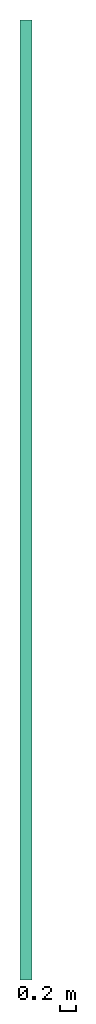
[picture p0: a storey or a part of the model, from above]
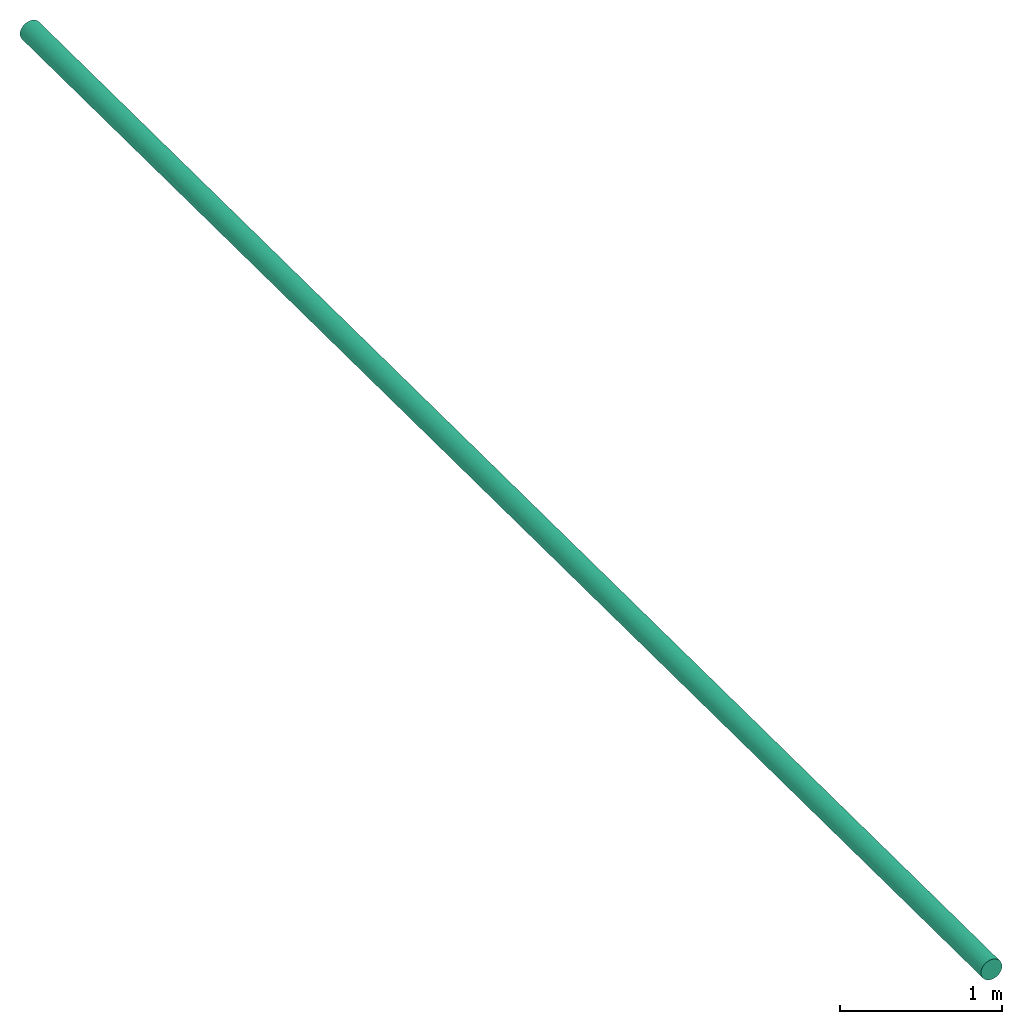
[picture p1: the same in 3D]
Properties of the parts of a building model (IFC2X3), part 1 of 2

# File
Description: ViewDefinition [CoordinationView_V2.0], RevitIdentifiers [ContentGUID: d610ecb9-631b-4e63-a7a0-f926296f45f9, VersionGUID: d526e5fb-8e76-41b3-b54c-00f57d6fdff5, NumberOfSaves: 322], CoordinateReference [CoordinateBase: Coordenadas compartilhadas]
File name: ABADIA_CEPAC_EX_DRE_PE_R01.ifc
Time: 2025-07-22T15:00:02-03:00
Written by: ODA SDAI 24.12
Made in: Autodesk Revit 25.4.0.32 (PTB) - IFC 25.4.0.32

# IfcProject, 01
LongName: CENTRO POLIVALENTE DE ATIVIDADES COMUNITÁRIAS PROF.° NELI ANTÔNIO DOS SANTOS | CEPAC DE ABADIA DE GOIÁS

# IfcSite, Default
RefLatitude: -22, -55, -4, -825807; RefLongitude: -43, -41, -10, -603150; RefElevation: 0 m

# IfcBuilding, CASA DE ACOLHIDA PARA IDOSOS
LongName: CASA DE ACOLHIDA PARA IDOSOS
Pset_BuildingCommon - NumberOfStoreys: 2

# IfcBuildingStorey: Nível:8mm Head (2)
In: CASA DE ACOLHIDA PARA IDOSOS
Name | LongName | Elevation (m)
IMPLANTAÇÃO DRENAGEM | IMPLANTAÇÃO DRENAGEM | -1.75
NIVEL 0 | NIVEL 0 | 0

# IfcBuildingElementProxy: Alvenaria prismática:Alvenaria prismática (3)
In: IMPLANTAÇÃO DRENAGEM
Type - Material: Alvenaria
Pset_BuildingElementProxyCommon - Reference: Alvenaria prismática; sets with these values: 2
Name (Alvenaria prismática:Alvenaria prismática:...)
28310843
28311744
28313048

# IfcBuildingElementProxy: Argamassa Impermeável Rampa (Inspeção):Argamassa Impermeável Rampa (Inspeção) (3)
In: IMPLANTAÇÃO DRENAGEM
Type - Material: Argamassa
Pset_BuildingElementProxyCommon - Reference: Argamassa Impermeável Rampa (Inspeção); sets with these values: 2
Name (Argamassa Impermeável Rampa (Inspeção):Argamassa Impermeável Rampa (Inspeção):...)
28310846
28311747
28313051

# IfcBuildingElementProxy: LXMMPED:LXMMPED, LXMMPED:LXMMPED:28396936
In: IMPLANTAÇÃO DRENAGEM
Type - Material: <Unnamed>
Pset_BuildingElementProxyCommon - Reference: LXMMPED; sets with these values: 2

# IfcBuildingElementProxy: Laje Concreto (Inspeção):Laje Concreto (Inspeção) (3)
In: IMPLANTAÇÃO DRENAGEM
Type - Material: Concreto
Pset_BuildingElementProxyCommon - Reference: Laje Concreto (Inspeção); sets with these values: 2
Name (Laje Concreto (Inspeção):Laje Concreto (Inspeção):...)
28310844
28311745
28313049

# IfcBuildingElementProxy: Tampa de Concreto com Grelha (Inspeção):Tampa de Concreto com Grelha (Inspeção) (3)
In: IMPLANTAÇÃO DRENAGEM
Type - Material: Aço, Concreto
Pset_BuildingElementProxyCommon - Reference: Tampa de Concreto com Grelha (Inspeção); sets with these values: 2
Name (Tampa de Concreto com Grelha (Inspeção):Tampa de Concreto com Grelha (Inspeção):...)
28310845
28311746
28313050

# IfcDistributionPort (886)
Description: Flow
Name | FlowDirection | Group
Port_28303643_0 | SOURCEANDSINK | Outro 1
Port_28303643_1 | SOURCEANDSINK | Outro 1
Port_28304500_0 | SOURCEANDSINK | Outro 2
Port_28304500_1 | SOURCEANDSINK | Outro 2
Port_28304754_0 | SOURCEANDSINK | Outro 5
Port_28304754_1 | SOURCEANDSINK | Outro 5
Port_28304825_0 | SOURCEANDSINK | Outro 4
Port_28304825_1 | SOURCEANDSINK | Outro 4
Port_28304847_0 | SOURCEANDSINK | Outro 8
Port_28304847_1 | SOURCEANDSINK | Outro 8
Port_28304869_0 | SOURCEANDSINK | Outro 10
Port_28304869_1 | SOURCEANDSINK | Outro 10
Port_28304983_0 | SOURCEANDSINK | Outro 7
Port_28304983_1 | SOURCEANDSINK | Outro 7
Port_28304996_0 | SOURCEANDSINK | Outro 9
Port_28304996_1 | SOURCEANDSINK | Outro 9
Port_28305340_0 | SOURCEANDSINK | Outro 18
Port_28305340_1 | SOURCEANDSINK | Outro 18
Port_28308791_0 | SOURCEANDSINK | Outro 17
Port_28308791_1 | SOURCEANDSINK | Outro 17
Port_28309445_0 | SOURCEANDSINK | Outro 6
Port_28309445_1 | SOURCEANDSINK | Outro 6
Port_28309447_0 | SOURCEANDSINK | Outro 11
Port_28309447_1 | SOURCEANDSINK | Outro 11
Port_28309449_0 | SOURCEANDSINK | Outro 12
Port_28309449_1 | SOURCEANDSINK | Outro 12
Port_28309451_0 | SOURCEANDSINK | Outro 13
Port_28309451_1 | SOURCEANDSINK | Outro 13
Port_28309453_0 | SOURCEANDSINK | Outro 14
Port_28309453_1 | SOURCEANDSINK | Outro 14
Port_28309455_0 | SOURCEANDSINK | Outro 15
Port_28309455_1 | SOURCEANDSINK | Outro 15
Port_28309488_0 | SOURCEANDSINK | Outro 16
Port_28309488_1 | SOURCEANDSINK | Outro 16
Port_28309490_0 | SOURCEANDSINK | Outro 19
Port_28309490_1 | SOURCEANDSINK | Outro 19
Port_28309492_0 | SOURCEANDSINK | Outro 20
Port_28309492_1 | SOURCEANDSINK | Outro 20
Port_28309494_0 | SOURCEANDSINK | Outro 21
Port_28309494_1 | SOURCEANDSINK | Outro 21
Port_28309496_0 | SOURCEANDSINK | Outro 22
Port_28309496_1 | SOURCEANDSINK | Outro 22
Port_28309498_0 | SOURCEANDSINK | Outro 23
Port_28309498_1 | SOURCEANDSINK | Outro 23
Port_28309500_0 | SOURCEANDSINK | Outro 24
Port_28309500_1 | SOURCEANDSINK | Outro 24
Port_28309502_0 | SOURCEANDSINK | Outro 25
Port_28309502_1 | SOURCEANDSINK | Outro 25
Port_28309504_0 | SOURCEANDSINK | Outro 26
Port_28309504_1 | SOURCEANDSINK | Outro 26
Port_28309506_0 | SOURCEANDSINK | Outro 27
Port_28309506_1 | SOURCEANDSINK | Outro 27
Port_28309508_0 | SOURCEANDSINK | Outro 28
Port_28309508_1 | SOURCEANDSINK | Outro 28
Port_28309510_0 | SOURCEANDSINK | Outro 29
Port_28309510_1 | SOURCEANDSINK | Outro 29
Port_28309580_0 | SOURCEANDSINK | Outro 30
Port_28309580_1 | SOURCEANDSINK | Outro 30
Port_28311791_0 | SOURCEANDSINK | Pluvial 1
Port_28311791_1 | SOURCEANDSINK | Pluvial 1
Port_28312506_0 | SOURCEANDSINK | Pluvial 2
Port_28312506_1 | SOURCEANDSINK | Pluvial 2
Port_28313325_0 | SOURCEANDSINK | Pluvial 4
Port_28313325_1 | SOURCEANDSINK | Pluvial 4
Port_28313540_0 | SOURCEANDSINK | Pluvial 5
Port_28313540_1 | SOURCEANDSINK | Pluvial 5
Port_28331878_0 | SOURCEANDSINK | Irrigação 1
Port_28368114_2 | SOURCEANDSINK | Irrigação 1
Port_28331878_1 | SOURCEANDSINK | Irrigação 1
Port_28368186_1 | SOURCEANDSINK | Irrigação 1
Port_28331994_0 | SOURCEANDSINK | Irrigação 1
Port_28368186_2 | SOURCEANDSINK | Irrigação 1
Port_28331994_1 | SOURCEANDSINK | Irrigação 1
Port_28332008_2 | SOURCEANDSINK | Irrigação 1
Port_28332002_0 | SOURCEANDSINK | Irrigação 1
Port_28332008_1 | SOURCEANDSINK | Irrigação 1
Port_28332002_1 | SOURCEANDSINK | Irrigação 1
Port_28332204_3 | SOURCEANDSINK | Irrigação 1
Port_28332010_0 | SOURCEANDSINK | Irrigação 1
Port_28360007_1 | SOURCEANDSINK | Irrigação 1
Port_28332010_1 | SOURCEANDSINK | Irrigação 1
Port_28351624_1 | SOURCEANDSINK | Irrigação 1
Port_28332204_1 | SOURCEANDSINK | Irrigação 1
Port_28351550_1 | SOURCEANDSINK | Irrigação 1
Port_28332204_2 | SOURCEANDSINK | Irrigação 1
Port_28332215_1 | SOURCEANDSINK | Irrigação 1
Port_28332215_0 | SOURCEANDSINK | Irrigação 1
Port_28360045_1 | SOURCEANDSINK | Irrigação 1
Port_28350503_1 | SOURCEANDSINK | Água fria e quente - Distribuição 3
Port_28350503_2 | SOURCEANDSINK
Port_28350503_3 | SOURCEANDSINK
Port_28350503_4 | SOURCEANDSINK
Port_28350503_5 | SOURCEANDSINK
OutPort_28350504_1 | SOURCE | Irrigação 13
OutPort_28350504_2 | SOURCE | Irrigação 13
Port_28350506_0 | SOURCEANDSINK | Irrigação 1
Port_28351127_1 | SOURCEANDSINK | Irrigação 1
Port_28350506_1 | SOURCEANDSINK | Irrigação 1
Port_28350508_1 | SOURCEANDSINK | Irrigação 1
Port_28350508_2 | SOURCEANDSINK | Irrigação 1
Port_28350514_0 | SOURCEANDSINK | Irrigação 1
OutPort_28350510_1 | SOURCE | Irrigação 17
OutPort_28350510_2 | SOURCE | Irrigação 17
Port_28350512_1 | SOURCEANDSINK | Irrigação 21
Port_28357601_0 | SOURCEANDSINK | Irrigação 21
Port_28350512_2 | SOURCEANDSINK | Irrigação 21
Port_28350516_0 | SOURCEANDSINK | Irrigação 21
Port_28350514_1 | SOURCEANDSINK | Irrigação 1
Port_28350516_1 | SOURCEANDSINK | Irrigação 21
Port_28351127_2 | SOURCEANDSINK | Irrigação 1
OutPort_28351133_1 | SOURCE | Irrigação 1
Port_28351133_2 | SOURCEANDSINK | Irrigação 1
Port_28359578_0 | SOURCEANDSINK | Irrigação 1
Port_28351550_0 | SOURCEANDSINK | Irrigação 1
Port_28360027_1 | SOURCEANDSINK | Irrigação 1
OutPort_28351624_2 | SOURCE | Irrigação 1
OutPort_28351626_1 | SOURCE | Irrigação 1
Port_28351626_2 | SOURCEANDSINK | Irrigação 1
Port_28357204_4 | SOURCEANDSINK
Port_28357355_1 | SOURCEANDSINK
Port_28357600_1 | SOURCEANDSINK | Irrigação 21
Port_28358009_0 | SOURCEANDSINK | Irrigação 21
Port_28357600_2 | SOURCEANDSINK | Irrigação 21
Port_28357601_1 | SOURCEANDSINK | Irrigação 21
OutPort_28357600_3 | SOURCE | Irrigação 21
Port_28357932_4 | SOURCEANDSINK
Port_28357933_1 | SOURCEANDSINK
Port_28357934_1 | SOURCEANDSINK | Irrigação 21
Port_28357934_2 | SOURCEANDSINK | Irrigação 21
Port_28358009_1 | SOURCEANDSINK | Irrigação 21
OutPort_28357934_3 | SOURCE | Irrigação 21
Port_28358085_4 | SOURCEANDSINK
Port_28358086_1 | SOURCEANDSINK
OutPort_28358087_1 | SOURCE | Irrigação 2
Port_28358087_2 | SOURCEANDSINK | Irrigação 2
Port_28358089_1 | SOURCEANDSINK | Irrigação 2
OutPort_28358087_3 | SOURCE | Irrigação 2
Port_28358089_0 | SOURCEANDSINK | Irrigação 2
Port_28358102_4 | SOURCEANDSINK
Port_28358103_1 | SOURCEANDSINK
OutPort_28358104_1 | SOURCE | Irrigação 3
Port_28358104_2 | SOURCEANDSINK | Irrigação 3
Port_28358106_1 | SOURCEANDSINK | Irrigação 3
OutPort_28358104_3 | SOURCE | Irrigação 3
Port_28358106_0 | SOURCEANDSINK | Irrigação 3
Port_28358117_4 | SOURCEANDSINK
Port_28358118_1 | SOURCEANDSINK
OutPort_28358119_1 | SOURCE | Irrigação 4
Port_28358119_2 | SOURCEANDSINK | Irrigação 4
Port_28358121_1 | SOURCEANDSINK | Irrigação 4
OutPort_28358119_3 | SOURCE | Irrigação 4
Port_28358121_0 | SOURCEANDSINK | Irrigação 4
Port_28358132_4 | SOURCEANDSINK
Port_28358133_1 | SOURCEANDSINK
OutPort_28358134_1 | SOURCE | Irrigação 5
Port_28358134_2 | SOURCEANDSINK | Irrigação 5
Port_28358136_1 | SOURCEANDSINK | Irrigação 5
Port_28358134_3 | SOURCEANDSINK | Irrigação 5
Port_28358136_0 | SOURCEANDSINK | Irrigação 5
Port_28358474_1 | SOURCEANDSINK | Irrigação 5
Port_28358145_4 | SOURCEANDSINK
Port_28358146_1 | SOURCEANDSINK
Port_28358147_1 | SOURCEANDSINK | Irrigação 6
Port_28358212_0 | SOURCEANDSINK | Irrigação 6
Port_28358147_2 | SOURCEANDSINK | Irrigação 6
Port_28358149_1 | SOURCEANDSINK | Irrigação 6
OutPort_28358147_3 | SOURCE | Irrigação 6
Port_28358149_0 | SOURCEANDSINK | Irrigação 6
Port_28358702_1 | SOURCEANDSINK | Irrigação 6
Port_28358208_4 | SOURCEANDSINK
Port_28358209_1 | SOURCEANDSINK
Port_28358212_1 | SOURCEANDSINK | Irrigação 6
Port_28359193_2 | SOURCEANDSINK | Irrigação 6
OutPort_28358474_2 | SOURCE | Irrigação 5
OutPort_28358702_2 | SOURCE | Irrigação 6
OutPort_28359193_1 | SOURCE | Irrigação 6
Port_28359470_1 | SOURCEANDSINK | Água fria e quente - Distribuição 1
Port_28359470_2 | SOURCEANDSINK
Port_28359470_3 | SOURCEANDSINK
Port_28359470_4 | SOURCEANDSINK
Port_28359470_5 | SOURCEANDSINK
OutPort_28359471_1 | SOURCE | Irrigação 7
OutPort_28359471_2 | SOURCE | Irrigação 7
Port_28359473_0 | SOURCEANDSINK | Irrigação 1
Port_28359577_3 | SOURCEANDSINK | Irrigação 1
Port_28359473_1 | SOURCEANDSINK | Irrigação 1
Port_28359475_1 | SOURCEANDSINK | Irrigação 1
Port_28359475_2 | SOURCEANDSINK | Irrigação 1
Port_28359481_0 | SOURCEANDSINK | Irrigação 1
OutPort_28359477_1 | SOURCE | Irrigação 9
OutPort_28359477_2 | SOURCE | Irrigação 9
Port_28359479_1 | SOURCEANDSINK | Irrigação 11
Port_28359488_0 | SOURCEANDSINK | Irrigação 11
Port_28359479_2 | SOURCEANDSINK | Irrigação 11
Port_28359483_0 | SOURCEANDSINK | Irrigação 11
Port_28359481_1 | SOURCEANDSINK | Irrigação 1
Port_28359483_1 | SOURCEANDSINK | Irrigação 11
Port_28359485_4 | SOURCEANDSINK
Port_28359486_1 | SOURCEANDSINK
Port_28359487_1 | SOURCEANDSINK | Irrigação 11
Port_28359495_0 | SOURCEANDSINK | Irrigação 11
Port_28359487_2 | SOURCEANDSINK | Irrigação 11
Port_28359488_1 | SOURCEANDSINK | Irrigação 11
OutPort_28359487_3 | SOURCE | Irrigação 11
Port_28359491_4 | SOURCEANDSINK
Port_28359492_1 | SOURCEANDSINK
OutPort_28359493_1 | SOURCE | Irrigação 11
Port_28359493_2 | SOURCEANDSINK | Irrigação 11
Port_28359495_1 | SOURCEANDSINK | Irrigação 11
OutPort_28359493_3 | SOURCE | Irrigação 11
Port_28359497_4 | SOURCEANDSINK
Port_28359498_1 | SOURCEANDSINK
OutPort_28359499_1 | SOURCE | Irrigação 15
Port_28359499_2 | SOURCEANDSINK | Irrigação 15
Port_28359501_1 | SOURCEANDSINK | Irrigação 15
OutPort_28359499_3 | SOURCE | Irrigação 15
Port_28359501_0 | SOURCEANDSINK | Irrigação 15
Port_28359503_4 | SOURCEANDSINK
Port_28359504_1 | SOURCEANDSINK
OutPort_28359505_1 | SOURCE | Irrigação 18
Port_28359505_2 | SOURCEANDSINK | Irrigação 18
Port_28359507_1 | SOURCEANDSINK | Irrigação 18
OutPort_28359505_3 | SOURCE | Irrigação 18
Port_28359507_0 | SOURCEANDSINK | Irrigação 18
Port_28359509_4 | SOURCEANDSINK
Port_28359510_1 | SOURCEANDSINK
OutPort_28359511_1 | SOURCE | Irrigação 20
Port_28359511_2 | SOURCEANDSINK | Irrigação 20
Port_28359513_1 | SOURCEANDSINK | Irrigação 20
OutPort_28359511_3 | SOURCE | Irrigação 20
Port_28359513_0 | SOURCEANDSINK | Irrigação 20
Port_28359515_4 | SOURCEANDSINK
Port_28359516_1 | SOURCEANDSINK
OutPort_28359517_1 | SOURCE | Irrigação 23
Port_28359517_2 | SOURCEANDSINK | Irrigação 23
Port_28359519_1 | SOURCEANDSINK | Irrigação 23
OutPort_28359517_3 | SOURCE | Irrigação 23
Port_28359519_0 | SOURCEANDSINK | Irrigação 23
Port_28359531_1 | SOURCEANDSINK | Irrigação 23
Port_28359521_4 | SOURCEANDSINK
Port_28359522_1 | SOURCEANDSINK
Port_28359523_1 | SOURCEANDSINK | Irrigação 24
Port_28359529_0 | SOURCEANDSINK | Irrigação 24
Port_28359523_2 | SOURCEANDSINK | Irrigação 24
Port_28359525_1 | SOURCEANDSINK | Irrigação 24
OutPort_28359523_3 | SOURCE | Irrigação 24
Port_28359525_0 | SOURCEANDSINK | Irrigação 24
Port_28359533_1 | SOURCEANDSINK | Irrigação 24
Port_28359527_4 | SOURCEANDSINK
Port_28359528_1 | SOURCEANDSINK
Port_28359529_1 | SOURCEANDSINK | Irrigação 24
Port_28359535_2 | SOURCEANDSINK | Irrigação 24
OutPort_28359531_2 | SOURCE | Irrigação 23
OutPort_28359533_2 | SOURCE | Irrigação 24
OutPort_28359535_1 | SOURCE | Irrigação 24
Port_28359577_1 | SOURCEANDSINK | Irrigação 1
Port_28360046_0 | SOURCEANDSINK | Irrigação 1
Port_28359577_2 | SOURCEANDSINK | Irrigação 1
Port_28359578_1 | SOURCEANDSINK | Irrigação 1
Port_28359605_1 | SOURCEANDSINK | Água fria e quente - Distribuição 2
Port_28359605_2 | SOURCEANDSINK
Port_28359605_3 | SOURCEANDSINK
Port_28359605_4 | SOURCEANDSINK
Port_28359605_5 | SOURCEANDSINK
OutPort_28359606_1 | SOURCE | Irrigação 8
OutPort_28359606_2 | SOURCE | Irrigação 8
Port_28359608_0 | SOURCEANDSINK | Irrigação 1
Port_28360045_3 | SOURCEANDSINK | Irrigação 1
Port_28359608_1 | SOURCEANDSINK | Irrigação 1
Port_28359610_1 | SOURCEANDSINK | Irrigação 1
Port_28359610_2 | SOURCEANDSINK | Irrigação 1
Port_28359616_0 | SOURCEANDSINK | Irrigação 1
OutPort_28359612_1 | SOURCE | Irrigação 12
OutPort_28359612_2 | SOURCE | Irrigação 12
Port_28359614_1 | SOURCEANDSINK | Irrigação 16
Port_28359623_0 | SOURCEANDSINK | Irrigação 16
Port_28359614_2 | SOURCEANDSINK | Irrigação 16
Port_28359618_0 | SOURCEANDSINK | Irrigação 16
Port_28359616_1 | SOURCEANDSINK | Irrigação 1
Port_28359618_1 | SOURCEANDSINK | Irrigação 16
Port_28359620_4 | SOURCEANDSINK
Port_28359621_1 | SOURCEANDSINK
Port_28359622_1 | SOURCEANDSINK | Irrigação 16
Port_28359630_0 | SOURCEANDSINK | Irrigação 16
Port_28359622_2 | SOURCEANDSINK | Irrigação 16
Port_28359623_1 | SOURCEANDSINK | Irrigação 16
OutPort_28359622_3 | SOURCE | Irrigação 16
Port_28359626_4 | SOURCEANDSINK
Port_28359627_1 | SOURCEANDSINK
OutPort_28359628_1 | SOURCE | Irrigação 16
Port_28359628_2 | SOURCEANDSINK | Irrigação 16
Port_28359630_1 | SOURCEANDSINK | Irrigação 16
OutPort_28359628_3 | SOURCE | Irrigação 16
Port_28359632_4 | SOURCEANDSINK
Port_28359633_1 | SOURCEANDSINK
OutPort_28359634_1 | SOURCE | Irrigação 25
Port_28359634_2 | SOURCEANDSINK | Irrigação 25
Port_28359636_1 | SOURCEANDSINK | Irrigação 25
OutPort_28359634_3 | SOURCE | Irrigação 25
Port_28359636_0 | SOURCEANDSINK | Irrigação 25
Port_28359638_4 | SOURCEANDSINK
Port_28359639_1 | SOURCEANDSINK
OutPort_28359640_1 | SOURCE | Irrigação 27
Port_28359640_2 | SOURCEANDSINK | Irrigação 27
Port_28359642_1 | SOURCEANDSINK | Irrigação 27
OutPort_28359640_3 | SOURCE | Irrigação 27
Port_28359642_0 | SOURCEANDSINK | Irrigação 27
Port_28359644_4 | SOURCEANDSINK
Port_28359645_1 | SOURCEANDSINK
OutPort_28359646_1 | SOURCE | Irrigação 29
Port_28359646_2 | SOURCEANDSINK | Irrigação 29
Port_28359648_1 | SOURCEANDSINK | Irrigação 29
OutPort_28359646_3 | SOURCE | Irrigação 29
Port_28359648_0 | SOURCEANDSINK | Irrigação 29
Port_28359650_4 | SOURCEANDSINK
Port_28359651_1 | SOURCEANDSINK
OutPort_28359652_1 | SOURCE | Irrigação 31
Port_28359652_2 | SOURCEANDSINK | Irrigação 31
Port_28359654_1 | SOURCEANDSINK | Irrigação 31
OutPort_28359652_3 | SOURCE | Irrigação 31
Port_28359654_0 | SOURCEANDSINK | Irrigação 31
Port_28359666_1 | SOURCEANDSINK | Irrigação 31
Port_28359656_4 | SOURCEANDSINK
Port_28359657_1 | SOURCEANDSINK
Port_28359658_1 | SOURCEANDSINK | Irrigação 32
Port_28359664_0 | SOURCEANDSINK | Irrigação 32
Port_28359658_2 | SOURCEANDSINK | Irrigação 32
Port_28359660_1 | SOURCEANDSINK | Irrigação 32
OutPort_28359658_3 | SOURCE | Irrigação 32
Port_28359660_0 | SOURCEANDSINK | Irrigação 32
Port_28359668_1 | SOURCEANDSINK | Irrigação 32
Port_28359662_4 | SOURCEANDSINK
Port_28359663_1 | SOURCEANDSINK
Port_28359664_1 | SOURCEANDSINK | Irrigação 32
Port_28359670_2 | SOURCEANDSINK | Irrigação 32
OutPort_28359666_2 | SOURCE | Irrigação 31
OutPort_28359668_2 | SOURCE | Irrigação 32
OutPort_28359670_1 | SOURCE | Irrigação 32
Port_28359702_1 | SOURCEANDSINK | Água fria e quente - Distribuição 4
Port_28359702_2 | SOURCEANDSINK
Port_28359702_3 | SOURCEANDSINK
Port_28359702_4 | SOURCEANDSINK
Port_28359702_5 | SOURCEANDSINK
OutPort_28359703_1 | SOURCE | Irrigação 14
OutPort_28359703_2 | SOURCE | Irrigação 14
Port_28359705_0 | SOURCEANDSINK | Irrigação 1
Port_28360027_3 | SOURCEANDSINK | Irrigação 1
Port_28359705_1 | SOURCEANDSINK | Irrigação 1
Port_28359707_1 | SOURCEANDSINK | Irrigação 1
Port_28359707_2 | SOURCEANDSINK | Irrigação 1
Port_28359713_0 | SOURCEANDSINK | Irrigação 1
OutPort_28359709_1 | SOURCE | Irrigação 22
OutPort_28359709_2 | SOURCE | Irrigação 22
Port_28359711_1 | SOURCEANDSINK | Irrigação 28
Port_28359720_0 | SOURCEANDSINK | Irrigação 28
Port_28359711_2 | SOURCEANDSINK | Irrigação 28
Port_28359715_0 | SOURCEANDSINK | Irrigação 28
Port_28359713_1 | SOURCEANDSINK | Irrigação 1
Port_28359715_1 | SOURCEANDSINK | Irrigação 28
Port_28359717_4 | SOURCEANDSINK
Port_28359718_1 | SOURCEANDSINK
Port_28359719_1 | SOURCEANDSINK | Irrigação 28
Port_28359727_0 | SOURCEANDSINK | Irrigação 28
Port_28359719_2 | SOURCEANDSINK | Irrigação 28
Port_28359720_1 | SOURCEANDSINK | Irrigação 28
OutPort_28359719_3 | SOURCE | Irrigação 28
Port_28359723_4 | SOURCEANDSINK
Port_28359724_1 | SOURCEANDSINK
OutPort_28359725_1 | SOURCE | Irrigação 28
Port_28359725_2 | SOURCEANDSINK | Irrigação 28
Port_28359727_1 | SOURCEANDSINK | Irrigação 28
OutPort_28359725_3 | SOURCE | Irrigação 28
Port_28359729_4 | SOURCEANDSINK
Port_28359730_1 | SOURCEANDSINK
OutPort_28359731_1 | SOURCE | Irrigação 34
Port_28359731_2 | SOURCEANDSINK | Irrigação 34
Port_28359733_1 | SOURCEANDSINK | Irrigação 34
OutPort_28359731_3 | SOURCE | Irrigação 34
Port_28359733_0 | SOURCEANDSINK | Irrigação 34
Port_28359735_4 | SOURCEANDSINK
Port_28359736_1 | SOURCEANDSINK
OutPort_28359737_1 | SOURCE | Irrigação 36
Port_28359737_2 | SOURCEANDSINK | Irrigação 36
Port_28359739_1 | SOURCEANDSINK | Irrigação 36
OutPort_28359737_3 | SOURCE | Irrigação 36
Port_28359739_0 | SOURCEANDSINK | Irrigação 36
Port_28359741_4 | SOURCEANDSINK
Port_28359742_1 | SOURCEANDSINK
OutPort_28359743_1 | SOURCE | Irrigação 38
Port_28359743_2 | SOURCEANDSINK | Irrigação 38
Port_28359745_1 | SOURCEANDSINK | Irrigação 38
OutPort_28359743_3 | SOURCE | Irrigação 38
Port_28359745_0 | SOURCEANDSINK | Irrigação 38
Port_28359747_4 | SOURCEANDSINK
Port_28359748_1 | SOURCEANDSINK
OutPort_28359749_1 | SOURCE | Irrigação 40
Port_28359749_2 | SOURCEANDSINK | Irrigação 40
Port_28359751_1 | SOURCEANDSINK | Irrigação 40
OutPort_28359749_3 | SOURCE | Irrigação 40
Port_28359751_0 | SOURCEANDSINK | Irrigação 40
Port_28359763_1 | SOURCEANDSINK | Irrigação 40
Port_28359753_4 | SOURCEANDSINK
Port_28359754_1 | SOURCEANDSINK
Port_28359755_1 | SOURCEANDSINK | Irrigação 41
Port_28359761_0 | SOURCEANDSINK | Irrigação 41
Port_28359755_2 | SOURCEANDSINK | Irrigação 41
Port_28359757_1 | SOURCEANDSINK | Irrigação 41
OutPort_28359755_3 | SOURCE | Irrigação 41
Port_28359757_0 | SOURCEANDSINK | Irrigação 41
Port_28359765_1 | SOURCEANDSINK | Irrigação 41
Port_28359759_4 | SOURCEANDSINK
Port_28359760_1 | SOURCEANDSINK
Port_28359761_1 | SOURCEANDSINK | Irrigação 41
Port_28359767_2 | SOURCEANDSINK | Irrigação 41
OutPort_28359763_2 | SOURCE | Irrigação 40
OutPort_28359765_2 | SOURCE | Irrigação 41
OutPort_28359767_1 | SOURCE | Irrigação 41
Port_28359799_1 | SOURCEANDSINK | Água fria e quente - Distribuição 5
Port_28359799_2 | SOURCEANDSINK
Port_28359799_3 | SOURCEANDSINK
Port_28359799_4 | SOURCEANDSINK
Port_28359799_5 | SOURCEANDSINK
OutPort_28359800_1 | SOURCE | Irrigação 26
OutPort_28359800_2 | SOURCE | Irrigação 26
Port_28359802_0 | SOURCEANDSINK | Irrigação 1
Port_28360007_3 | SOURCEANDSINK | Irrigação 1
Port_28359802_1 | SOURCEANDSINK | Irrigação 1
Port_28359804_1 | SOURCEANDSINK | Irrigação 1
Port_28359804_2 | SOURCEANDSINK | Irrigação 1
Port_28359810_0 | SOURCEANDSINK | Irrigação 1
OutPort_28359806_1 | SOURCE | Irrigação 33
OutPort_28359806_2 | SOURCE | Irrigação 33
Port_28359808_1 | SOURCEANDSINK | Irrigação 37
Port_28359817_0 | SOURCEANDSINK | Irrigação 37
Port_28359808_2 | SOURCEANDSINK | Irrigação 37
Port_28359812_0 | SOURCEANDSINK | Irrigação 37
Port_28359810_1 | SOURCEANDSINK | Irrigação 1
Port_28359812_1 | SOURCEANDSINK | Irrigação 37
Port_28359814_4 | SOURCEANDSINK
Port_28359815_1 | SOURCEANDSINK
Port_28359816_1 | SOURCEANDSINK | Irrigação 37
Port_28359824_0 | SOURCEANDSINK | Irrigação 37
Port_28359816_2 | SOURCEANDSINK | Irrigação 37
Port_28359817_1 | SOURCEANDSINK | Irrigação 37
OutPort_28359816_3 | SOURCE | Irrigação 37
Port_28359820_4 | SOURCEANDSINK
Port_28359821_1 | SOURCEANDSINK
OutPort_28359822_1 | SOURCE | Irrigação 37
Port_28359822_2 | SOURCEANDSINK | Irrigação 37
Port_28359824_1 | SOURCEANDSINK | Irrigação 37
OutPort_28359822_3 | SOURCE | Irrigação 37
Port_28359826_4 | SOURCEANDSINK
Port_28359827_1 | SOURCEANDSINK
OutPort_28359828_1 | SOURCE | Irrigação 43
Port_28359828_2 | SOURCEANDSINK | Irrigação 43
Port_28359830_1 | SOURCEANDSINK | Irrigação 43
OutPort_28359828_3 | SOURCE | Irrigação 43
Port_28359830_0 | SOURCEANDSINK | Irrigação 43
Port_28359832_4 | SOURCEANDSINK
Port_28359833_1 | SOURCEANDSINK
OutPort_28359834_1 | SOURCE | Irrigação 45
Port_28359834_2 | SOURCEANDSINK | Irrigação 45
Port_28359836_1 | SOURCEANDSINK | Irrigação 45
OutPort_28359834_3 | SOURCE | Irrigação 45
Port_28359836_0 | SOURCEANDSINK | Irrigação 45
Port_28359838_4 | SOURCEANDSINK
Port_28359839_1 | SOURCEANDSINK
OutPort_28359840_1 | SOURCE | Irrigação 47
Port_28359840_2 | SOURCEANDSINK | Irrigação 47
Port_28359842_1 | SOURCEANDSINK | Irrigação 47
OutPort_28359840_3 | SOURCE | Irrigação 47
Port_28359842_0 | SOURCEANDSINK | Irrigação 47
Port_28359844_4 | SOURCEANDSINK
Port_28359845_1 | SOURCEANDSINK
OutPort_28359846_1 | SOURCE | Irrigação 49
Port_28359846_2 | SOURCEANDSINK | Irrigação 49
Port_28359848_1 | SOURCEANDSINK | Irrigação 49
OutPort_28359846_3 | SOURCE | Irrigação 49
Port_28359848_0 | SOURCEANDSINK | Irrigação 49
Port_28359860_1 | SOURCEANDSINK | Irrigação 49
Port_28359850_4 | SOURCEANDSINK
Port_28359851_1 | SOURCEANDSINK
Port_28359852_1 | SOURCEANDSINK | Irrigação 50
Port_28359858_0 | SOURCEANDSINK | Irrigação 50
Port_28359852_2 | SOURCEANDSINK | Irrigação 50
Port_28359854_1 | SOURCEANDSINK | Irrigação 50
OutPort_28359852_3 | SOURCE | Irrigação 50
Port_28359854_0 | SOURCEANDSINK | Irrigação 50
Port_28359862_1 | SOURCEANDSINK | Irrigação 50
Port_28359856_4 | SOURCEANDSINK
Port_28359857_1 | SOURCEANDSINK
Port_28359858_1 | SOURCEANDSINK | Irrigação 50
Port_28359864_2 | SOURCEANDSINK | Irrigação 50
OutPort_28359860_2 | SOURCE | Irrigação 49
OutPort_28359862_2 | SOURCE | Irrigação 50
OutPort_28359864_1 | SOURCE | Irrigação 50
Port_28359896_1 | SOURCEANDSINK | Água fria e quente - Distribuição 6
Port_28359896_2 | SOURCEANDSINK
Port_28359896_3 | SOURCEANDSINK
Port_28359896_4 | SOURCEANDSINK
Port_28359896_5 | SOURCEANDSINK
OutPort_28359897_1 | SOURCE | Irrigação 35
OutPort_28359897_2 | SOURCE | Irrigação 35
Port_28359899_0 | SOURCEANDSINK | Irrigação 39
Port_28359899_1 | SOURCEANDSINK | Irrigação 39
Port_28359901_1 | SOURCEANDSINK | Irrigação 39
Port_28359901_2 | SOURCEANDSINK | Irrigação 39
Port_28359907_0 | SOURCEANDSINK | Irrigação 39
OutPort_28359903_1 | SOURCE | Irrigação 42
OutPort_28359903_2 | SOURCE | Irrigação 42
Port_28359905_1 | SOURCEANDSINK | Irrigação 46
Port_28359914_0 | SOURCEANDSINK | Irrigação 46
Port_28359905_2 | SOURCEANDSINK | Irrigação 46
Port_28359909_0 | SOURCEANDSINK | Irrigação 46
Port_28359907_1 | SOURCEANDSINK | Irrigação 39
Port_28359909_1 | SOURCEANDSINK | Irrigação 46
Port_28359911_4 | SOURCEANDSINK
Port_28359912_1 | SOURCEANDSINK
Port_28359913_1 | SOURCEANDSINK | Irrigação 46
Port_28359921_0 | SOURCEANDSINK | Irrigação 46
Port_28359913_2 | SOURCEANDSINK | Irrigação 46
Port_28359914_1 | SOURCEANDSINK | Irrigação 46
OutPort_28359913_3 | SOURCE | Irrigação 46
Port_28359917_4 | SOURCEANDSINK
Port_28359918_1 | SOURCEANDSINK
OutPort_28359919_1 | SOURCE | Irrigação 46
Port_28359919_2 | SOURCEANDSINK | Irrigação 46
Port_28359921_1 | SOURCEANDSINK | Irrigação 46
OutPort_28359919_3 | SOURCE | Irrigação 46
Port_28359923_4 | SOURCEANDSINK
Port_28359924_1 | SOURCEANDSINK
OutPort_28359925_1 | SOURCE | Irrigação 52
Port_28359925_2 | SOURCEANDSINK | Irrigação 52
Port_28359927_1 | SOURCEANDSINK | Irrigação 52
OutPort_28359925_3 | SOURCE | Irrigação 52
Port_28359927_0 | SOURCEANDSINK | Irrigação 52
Port_28359929_4 | SOURCEANDSINK
Port_28359930_1 | SOURCEANDSINK
OutPort_28359931_1 | SOURCE | Irrigação 54
Port_28359931_2 | SOURCEANDSINK | Irrigação 54
Port_28359933_1 | SOURCEANDSINK | Irrigação 54
OutPort_28359931_3 | SOURCE | Irrigação 54
Port_28359933_0 | SOURCEANDSINK | Irrigação 54
Port_28359935_4 | SOURCEANDSINK
Port_28359936_1 | SOURCEANDSINK
OutPort_28359937_1 | SOURCE | Irrigação 56
Port_28359937_2 | SOURCEANDSINK | Irrigação 56
Port_28359939_1 | SOURCEANDSINK | Irrigação 56
OutPort_28359937_3 | SOURCE | Irrigação 56
Port_28359939_0 | SOURCEANDSINK | Irrigação 56
Port_28359941_4 | SOURCEANDSINK
Port_28359942_1 | SOURCEANDSINK
OutPort_28359943_1 | SOURCE | Irrigação 58
Port_28359943_2 | SOURCEANDSINK | Irrigação 58
Port_28359945_1 | SOURCEANDSINK | Irrigação 58
OutPort_28359943_3 | SOURCE | Irrigação 58
Port_28359945_0 | SOURCEANDSINK | Irrigação 58
Port_28359957_1 | SOURCEANDSINK | Irrigação 58
Port_28359947_4 | SOURCEANDSINK
Port_28359948_1 | SOURCEANDSINK
Port_28359949_1 | SOURCEANDSINK | Irrigação 59
Port_28359955_0 | SOURCEANDSINK | Irrigação 59
Port_28359949_2 | SOURCEANDSINK | Irrigação 59
Port_28359951_1 | SOURCEANDSINK | Irrigação 59
OutPort_28359949_3 | SOURCE | Irrigação 59
Port_28359951_0 | SOURCEANDSINK | Irrigação 59
Port_28359959_1 | SOURCEANDSINK | Irrigação 59
Port_28359953_4 | SOURCEANDSINK
Port_28359954_1 | SOURCEANDSINK
Port_28359955_1 | SOURCEANDSINK | Irrigação 59
Port_28359961_2 | SOURCEANDSINK | Irrigação 59
OutPort_28359957_2 | SOURCE | Irrigação 58
OutPort_28359959_2 | SOURCE | Irrigação 59
OutPort_28359961_1 | SOURCE | Irrigação 59
Port_28360007_2 | SOURCEANDSINK | Irrigação 1
Port_28360028_0 | SOURCEANDSINK | Irrigação 1
Port_28360027_2 | SOURCEANDSINK | Irrigação 1
Port_28360028_1 | SOURCEANDSINK | Irrigação 1
Port_28360045_2 | SOURCEANDSINK | Irrigação 1
Port_28360046_1 | SOURCEANDSINK | Irrigação 1
OutPort_28360117_1 | SOURCE
Port_28360117_2 | SOURCEANDSINK | Água fria e quente - Distribuição 8
Port_28371629_0 | SOURCEANDSINK | Água fria e quente - Distribuição 8
Port_28360117_3 | SOURCEANDSINK | Água fria e quente - Distribuição 9
Port_28371257_0 | SOURCEANDSINK | Água fria e quente - Distribuição 9
OutPort_28360117_4 | SOURCE
OutPort_28360117_5 | SOURCE | Água fria e quente - Distribuição 11
InPort_28370632_0 | SINK | Água fria e quente - Distribuição 8
OutPort_28360117_6 | SOURCE | Água fria e quente - Distribuição 8
InPort_28362233_0 | SINK | Água fria e quente - Distribuição 8
OutPort_28360117_7 | SOURCE | Água fria e quente - Distribuição 8
OutPort_28360117_8 | SOURCE | Água fria e quente - Distribuição 7
Port_28360371_1 | SOURCEANDSINK
Port_28360375_1 | SOURCEANDSINK
OutPort_28360491_1 | SOURCE
Port_28360491_2 | SOURCEANDSINK | Água fria e quente - Distribuição 8
Port_28362430_1 | SOURCEANDSINK | Água fria e quente - Distribuição 8
OutPort_28360491_3 | SOURCE
Port_28360491_4 | SOURCEANDSINK | Água fria e quente - Distribuição 9
Port_28371298_0 | SOURCEANDSINK | Água fria e quente - Distribuição 9
OutPort_28360491_5 | SOURCE
InPort_28362357_1 | SINK | Água fria e quente - Distribuição 8
OutPort_28360491_6 | SOURCE | Água fria e quente - Distribuição 8
OutPort_28360491_7 | SOURCE | Água fria e quente - Distribuição 10
InPort_28362200_0 | SINK | Água fria e quente - Distribuição 8
OutPort_28360491_8 | SOURCE | Água fria e quente - Distribuição 8
Port_28360496_1 | SOURCEANDSINK
InPort_28362092_0 | SINK | Água fria e quente - Distribuição 8
OutPort_28362231_1 | SOURCE | Água fria e quente - Distribuição 8
InPort_28370257_1 | SINK | Água fria e quente - Distribuição 8
OutPort_28362092_1 | SOURCE | Água fria e quente - Distribuição 8
InPort_28362131_0 | SINK | Água fria e quente - Distribuição 8
OutPort_28362198_1 | SOURCE | Água fria e quente - Distribuição 8
InPort_28370259_2 | SINK | Água fria e quente - Distribuição 8
OutPort_28362131_1 | SOURCE | Água fria e quente - Distribuição 8
InPort_28362198_2 | SINK | Água fria e quente - Distribuição 8
OutPort_28362200_1 | SOURCE | Água fria e quente - Distribuição 8
InPort_28362231_2 | SINK | Água fria e quente - Distribuição 8
OutPort_28362233_1 | SOURCE | Água fria e quente - Distribuição 8
InPort_28370612_1 | SINK | Água fria e quente - Distribuição 8
OutPort_28362357_0 | SOURCE | Água fria e quente - Distribuição 8
Port_28362430_0 | SOURCEANDSINK | Água fria e quente - Distribuição 8
Port_28371628_1 | SOURCEANDSINK | Água fria e quente - Distribuição 8
InPort_28362554_1 | SINK | Água fria e quente - Distribuição 8
OutPort_28362555_1 | SOURCE | Água fria e quente - Distribuição 8
InPort_28362554_2 | SINK | Água fria e quente - Distribuição 8
OutPort_28370614_0 | SOURCE | Água fria e quente - Distribuição 8
InPort_28362955_0 | SINK | Água fria e quente - Distribuição 8
OutPort_28362554_3 | SOURCE | Água fria e quente - Distribuição 8
InPort_28362555_0 | SINK | Água fria e quente - Distribuição 8
OutPort_28370630_1 | SOURCE | Água fria e quente - Distribuição 8
InPort_28362969_1 | SINK | Água fria e quente - Distribuição 8
OutPort_28362955_1 | SOURCE | Água fria e quente - Distribuição 8
InPort_28362961_0 | SINK | Água fria e quente - Distribuição 8
OutPort_28370936_1 | SOURCE | Água fria e quente - Distribuição 8
InPort_28362979_2 | SINK | Água fria e quente - Distribuição 8
OutPort_28362961_1 | SOURCE | Água fria e quente - Distribuição 8
InPort_28370938_0 | SINK | Água fria e quente - Distribuição 8
OutPort_28362969_2 | SOURCE | Água fria e quente - Distribuição 8
InPort_28363507_0 | SINK | Água fria e quente - Distribuição 8
OutPort_28362979_1 | SOURCE | Água fria e quente - Distribuição 8
InPort_28363414_0 | SINK | Água fria e quente - Distribuição 8
OutPort_28363578_2 | SOURCE | Água fria e quente - Distribuição 8
InPort_28363624_1 | SINK | Água fria e quente - Distribuição 8
OutPort_28363414_1 | SOURCE | Água fria e quente - Distribuição 8
InPort_28363578_1 | SINK | Água fria e quente - Distribuição 8
OutPort_28363507_1 | SOURCE | Água fria e quente - Distribuição 8
InPort_28363627_1 | SINK | Água fria e quente - Distribuição 8
OutPort_28363624_2 | SOURCE | Água fria e quente - Distribuição 8
OutPort_28363627_0 | SOURCE | Água fria e quente - Distribuição 8
Port_28364081_0 | SOURCEANDSINK | Irrigação 1
Port_28370908_1 | SOURCEANDSINK | Irrigação 1
Port_28364081_1 | SOURCEANDSINK | Irrigação 1
Port_28368110_1 | SOURCEANDSINK | Irrigação 1
Port_28364225_0 | SOURCEANDSINK | Irrigação 1
Port_28368008_2 | SOURCEANDSINK | Irrigação 1
Port_28364225_1 | SOURCEANDSINK | Irrigação 1
Port_28368012_1 | SOURCEANDSINK | Irrigação 1
InPort_28367458_1 | SINK | Água fria e quente - Distribuição 14
OutPort_28367805_1 | SOURCE | Irrigação 1
Port_28367805_2 | SOURCEANDSINK | Irrigação 1
Port_28367874_0 | SOURCEANDSINK | Irrigação 1
Port_28367871_1 | SOURCEANDSINK | Irrigação 1
Port_28367900_0 | SOURCEANDSINK | Irrigação 1
Port_28367871_2 | SOURCEANDSINK | Irrigação 1
Port_28367874_1 | SOURCEANDSINK | Irrigação 1
Port_28367899_1 | SOURCEANDSINK | Irrigação 1
Port_28367900_1 | SOURCEANDSINK | Irrigação 1
Port_28367899_2 | SOURCEANDSINK | Irrigação 1
Port_28367967_0 | SOURCEANDSINK | Irrigação 1
OutPort_28367899_3 | SOURCE | Irrigação 1
Port_28367967_1 | SOURCEANDSINK | Irrigação 1
Port_28368012_2 | SOURCEANDSINK | Irrigação 1
Port_28368008_1 | SOURCEANDSINK | Irrigação 1
Port_28370910_0 | SOURCEANDSINK | Irrigação 1
Port_28368108_0 | SOURCEANDSINK | Irrigação 1
Port_28368110_2 | SOURCEANDSINK | Irrigação 1
Port_28368108_1 | SOURCEANDSINK | Irrigação 1
Port_28368114_1 | SOURCEANDSINK | Irrigação 1
InPort_28370279_2 | SINK | Água fria e quente - Distribuição 8
OutPort_28370243_0 | SOURCE | Água fria e quente - Distribuição 8
InPort_28370243_1 | SINK | Água fria e quente - Distribuição 8
OutPort_28370259_1 | SOURCE | Água fria e quente - Distribuição 8
InPort_28370280_0 | SINK | Água fria e quente - Distribuição 8
OutPort_28370257_2 | SOURCE | Água fria e quente - Distribuição 8
InPort_28370267_0 | SINK | Água fria e quente - Distribuição 8
OutPort_28370279_3 | SOURCE | Água fria e quente - Distribuição 8
InPort_28371173_1 | SINK | Água fria e quente - Distribuição 8
OutPort_28370267_1 | SOURCE | Água fria e quente - Distribuição 8
InPort_28370279_1 | SINK | Água fria e quente - Distribuição 8
OutPort_28370280_1 | SOURCE | Água fria e quente - Distribuição 8
InPort_28370614_1 | SINK | Água fria e quente - Distribuição 8
OutPort_28370612_2 | SOURCE | Água fria e quente - Distribuição 8
InPort_28370630_2 | SINK | Água fria e quente - Distribuição 8
OutPort_28370632_1 | SOURCE | Água fria e quente - Distribuição 8
Port_28370908_2 | SOURCEANDSINK | Irrigação 1
Port_28370910_1 | SOURCEANDSINK | Irrigação 1
InPort_28370936_2 | SINK | Água fria e quente - Distribuição 8
OutPort_28370938_1 | SOURCE | Água fria e quente - Distribuição 8
Port_28371160_0 | SOURCEANDSINK | Água fria e quente - Distribuição 8
Port_28371464_1 | SOURCEANDSINK | Água fria e quente - Distribuição 8
Port_28371160_1 | SOURCEANDSINK | Água fria e quente - Distribuição 8
Port_28371173_3 | SOURCEANDSINK | Água fria e quente - Distribuição 8
Port_28371173_2 | SOURCEANDSINK | Água fria e quente - Distribuição 8
Port_28371192_0 | SOURCEANDSINK | Água fria e quente - Distribuição 8
Port_28371192_1 | SOURCEANDSINK | Água fria e quente - Distribuição 8
Port_28371257_1 | SOURCEANDSINK | Água fria e quente - Distribuição 9
Port_28371330_1 | SOURCEANDSINK | Água fria e quente - Distribuição 9
Port_28371298_1 | SOURCEANDSINK | Água fria e quente - Distribuição 9
Port_28371332_2 | SOURCEANDSINK | Água fria e quente - Distribuição 9
Port_28371310_0 | SOURCEANDSINK | Água fria e quente - Distribuição 9
Port_28372723_1 | SOURCEANDSINK | Água fria e quente - Distribuição 9
Port_28371310_1 | SOURCEANDSINK | Água fria e quente - Distribuição 9
Port_28371332_1 | SOURCEANDSINK | Água fria e quente - Distribuição 9
Port_28371330_2 | SOURCEANDSINK | Água fria e quente - Distribuição 9
Port_28372724_0 | SOURCEANDSINK | Água fria e quente - Distribuição 9
Port_28371464_2 | SOURCEANDSINK | Água fria e quente - Distribuição 8
Port_28371674_0 | SOURCEANDSINK | Água fria e quente - Distribuição 8
Port_28371603_0 | SOURCEANDSINK | Água fria e quente - Distribuição 8
Port_28371628_3 | SOURCEANDSINK | Água fria e quente - Distribuição 8
Port_28371603_1 | SOURCEANDSINK | Água fria e quente - Distribuição 8
Port_28371736_1 | SOURCEANDSINK | Água fria e quente - Distribuição 8
Port_28371628_2 | SOURCEANDSINK | Água fria e quente - Distribuição 8
Port_28371629_1 | SOURCEANDSINK | Água fria e quente - Distribuição 8
Port_28371674_1 | SOURCEANDSINK | Água fria e quente - Distribuição 8
Port_28371736_2 | SOURCEANDSINK | Água fria e quente - Distribuição 8
Port_28372707_0 | SOURCEANDSINK | Água fria e quente - Distribuição 9
Port_28372723_3 | SOURCEANDSINK | Água fria e quente - Distribuição 9
Port_28372707_1 | SOURCEANDSINK | Água fria e quente - Distribuição 9
Port_28372723_2 | SOURCEANDSINK | Água fria e quente - Distribuição 9
Port_28372724_1 | SOURCEANDSINK | Água fria e quente - Distribuição 9
Port_28396927_1 | SOURCEANDSINK
Port_28396927_2 | SOURCEANDSINK
Port_28396927_3 | SOURCEANDSINK
Port_28396927_4 | SOURCEANDSINK
Port_28403089_1 | SOURCEANDSINK
Port_28403089_2 | SOURCEANDSINK
Port_28413112_1 | SOURCEANDSINK | Outro 45
Port_28413112_2 | SOURCEANDSINK | Outro 45
Port_28413112_3 | SOURCEANDSINK | Outro 45
Port_28413114_1 | SOURCEANDSINK
Port_28413114_2 | SOURCEANDSINK
Port_28413122_1 | SOURCEANDSINK | Outro 46
Port_28413122_2 | SOURCEANDSINK | Outro 46
Port_28413122_3 | SOURCEANDSINK | Outro 46
Port_28413124_1 | SOURCEANDSINK
Port_28413124_2 | SOURCEANDSINK
Port_28413455_1 | SOURCEANDSINK | Outro 43
Port_28413455_2 | SOURCEANDSINK | Outro 43
Port_28413455_3 | SOURCEANDSINK | Outro 43
Port_28413457_1 | SOURCEANDSINK
Port_28413457_2 | SOURCEANDSINK
Port_28413465_1 | SOURCEANDSINK | Outro 44
Port_28413465_2 | SOURCEANDSINK | Outro 44
Port_28413465_3 | SOURCEANDSINK | Outro 44
Port_28413467_1 | SOURCEANDSINK
Port_28413467_2 | SOURCEANDSINK
Port_28413519_1 | SOURCEANDSINK | Outro 41
Port_28413519_2 | SOURCEANDSINK | Outro 41
Port_28413519_3 | SOURCEANDSINK | Outro 41
Port_28413521_1 | SOURCEANDSINK
Port_28413521_2 | SOURCEANDSINK
Port_28413529_1 | SOURCEANDSINK | Outro 42
Port_28413529_2 | SOURCEANDSINK | Outro 42
Port_28413529_3 | SOURCEANDSINK | Outro 42
Port_28413531_1 | SOURCEANDSINK
Port_28413531_2 | SOURCEANDSINK
Port_28413572_1 | SOURCEANDSINK | Outro 39
Port_28413572_2 | SOURCEANDSINK | Outro 39
Port_28413572_3 | SOURCEANDSINK | Outro 39
Port_28413574_1 | SOURCEANDSINK
Port_28413574_2 | SOURCEANDSINK
Port_28413582_1 | SOURCEANDSINK | Outro 40
Port_28413582_2 | SOURCEANDSINK | Outro 40
Port_28413582_3 | SOURCEANDSINK | Outro 40
Port_28413584_1 | SOURCEANDSINK
Port_28413584_2 | SOURCEANDSINK
Port_28413615_1 | SOURCEANDSINK | Outro 37
Port_28413615_2 | SOURCEANDSINK | Outro 37
Port_28413615_3 | SOURCEANDSINK | Outro 37
Port_28413617_1 | SOURCEANDSINK
Port_28413617_2 | SOURCEANDSINK
Port_28413625_1 | SOURCEANDSINK | Outro 38
Port_28413625_2 | SOURCEANDSINK | Outro 38
Port_28413625_3 | SOURCEANDSINK | Outro 38
Port_28413627_1 | SOURCEANDSINK
Port_28413627_2 | SOURCEANDSINK
Port_28413721_1 | SOURCEANDSINK | Outro 47
Port_28413721_2 | SOURCEANDSINK | Outro 47
Port_28413721_3 | SOURCEANDSINK | Outro 47
Port_28413723_1 | SOURCEANDSINK
Port_28413723_2 | SOURCEANDSINK
Port_28413731_1 | SOURCEANDSINK | Outro 48
Port_28413731_2 | SOURCEANDSINK | Outro 48
Port_28413731_3 | SOURCEANDSINK | Outro 48
Port_28413733_1 | SOURCEANDSINK
Port_28413733_2 | SOURCEANDSINK
Port_28413847_1 | SOURCEANDSINK | Outro 31
Port_28413847_2 | SOURCEANDSINK | Outro 31
Port_28413847_3 | SOURCEANDSINK | Outro 31
Port_28413849_1 | SOURCEANDSINK
Port_28413849_2 | SOURCEANDSINK
Port_28413857_1 | SOURCEANDSINK | Outro 32
Port_28413857_2 | SOURCEANDSINK | Outro 32
Port_28413857_3 | SOURCEANDSINK | Outro 32
Port_28413859_1 | SOURCEANDSINK
Port_28413859_2 | SOURCEANDSINK
Port_28413900_1 | SOURCEANDSINK | Outro 33
Port_28413900_2 | SOURCEANDSINK | Outro 33
Port_28413900_3 | SOURCEANDSINK | Outro 33
Port_28413902_1 | SOURCEANDSINK
Port_28413902_2 | SOURCEANDSINK
Port_28413910_1 | SOURCEANDSINK | Outro 34
Port_28413910_2 | SOURCEANDSINK | Outro 34
Port_28413910_3 | SOURCEANDSINK | Outro 34
Port_28413912_1 | SOURCEANDSINK
Port_28413912_2 | SOURCEANDSINK
Port_28413920_1 | SOURCEANDSINK | Outro 35
Port_28413920_2 | SOURCEANDSINK | Outro 35
Port_28413920_3 | SOURCEANDSINK | Outro 35
Port_28413922_1 | SOURCEANDSINK
Port_28413922_2 | SOURCEANDSINK
Port_28413930_1 | SOURCEANDSINK | Outro 36
Port_28413930_2 | SOURCEANDSINK | Outro 36
Port_28413930_3 | SOURCEANDSINK | Outro 36
Port_28413932_1 | SOURCEANDSINK
Port_28413932_2 | SOURCEANDSINK
Port_28413940_1 | SOURCEANDSINK | Outro 49
Port_28413940_2 | SOURCEANDSINK | Outro 49
Port_28413940_3 | SOURCEANDSINK | Outro 49
Port_28413942_1 | SOURCEANDSINK
Port_28413942_2 | SOURCEANDSINK
Port_28413950_1 | SOURCEANDSINK | Outro 50
Port_28413950_2 | SOURCEANDSINK | Outro 50
Port_28413950_3 | SOURCEANDSINK | Outro 50
Port_28413952_1 | SOURCEANDSINK
Port_28413952_2 | SOURCEANDSINK
Port_28413960_1 | SOURCEANDSINK | Outro 51
Port_28413960_2 | SOURCEANDSINK | Outro 51
Port_28413960_3 | SOURCEANDSINK | Outro 51
Port_28413962_1 | SOURCEANDSINK
Port_28413962_2 | SOURCEANDSINK
Port_28413970_1 | SOURCEANDSINK | Outro 52
Port_28413970_2 | SOURCEANDSINK | Outro 52
Port_28413970_3 | SOURCEANDSINK | Outro 52
Port_28413972_1 | SOURCEANDSINK
Port_28413972_2 | SOURCEANDSINK
Port_28413980_1 | SOURCEANDSINK | Outro 53
Port_28413980_2 | SOURCEANDSINK | Outro 53
Port_28413980_3 | SOURCEANDSINK | Outro 53
Port_28413982_1 | SOURCEANDSINK
Port_28413982_2 | SOURCEANDSINK
Port_28413990_1 | SOURCEANDSINK | Outro 54
Port_28413990_2 | SOURCEANDSINK | Outro 54
Port_28413990_3 | SOURCEANDSINK | Outro 54
Port_28413992_1 | SOURCEANDSINK
Port_28413992_2 | SOURCEANDSINK
Port_28414000_1 | SOURCEANDSINK | Outro 55
Port_28414000_2 | SOURCEANDSINK | Outro 55
Port_28414000_3 | SOURCEANDSINK | Outro 55
Port_28414002_1 | SOURCEANDSINK
Port_28414002_2 | SOURCEANDSINK
Port_28414010_1 | SOURCEANDSINK | Outro 56
Port_28414010_2 | SOURCEANDSINK | Outro 56
Port_28414010_3 | SOURCEANDSINK | Outro 56
Port_28414012_1 | SOURCEANDSINK
Port_28414012_2 | SOURCEANDSINK
Port_28414020_1 | SOURCEANDSINK | Outro 57
Port_28414020_2 | SOURCEANDSINK | Outro 57
Port_28414020_3 | SOURCEANDSINK | Outro 57
Port_28414022_1 | SOURCEANDSINK
Port_28414022_2 | SOURCEANDSINK
Port_28414030_1 | SOURCEANDSINK | Outro 58
Port_28414030_2 | SOURCEANDSINK | Outro 58
Port_28414030_3 | SOURCEANDSINK | Outro 58
Port_28414032_1 | SOURCEANDSINK
Port_28414032_2 | SOURCEANDSINK
Port_28415915_0 | SOURCEANDSINK | Pluvial 6
Port_28415915_1 | SOURCEANDSINK | Pluvial 6
Port_28416132_0 | SOURCEANDSINK | Outro 59
Port_28416132_1 | SOURCEANDSINK | Outro 59
Port_28418382_1 | SOURCEANDSINK
Port_28418450_1 | SOURCEANDSINK
Port_28418604_1 | SOURCEANDSINK
Port_28419284_1 | SOURCEANDSINK
Port_28419288_1 | SOURCEANDSINK

# IfcFlowController: AF_Registro Esfera VS:Soldável - 75 mm (6)
In: IMPLANTAÇÃO DRENAGEM
Type - Material: Phenolic Resin, PVC Marrom
Type - Pset_ManufacturerTypeInformation - Manufacturer: © Tigre S/A
Pset_DistributionFlowElementCommon - Reference: Soldável - 75 mm; sets with these values: 2
Name (AF_Registro Esfera VS:Soldável - 75 mm:...) | Group
28362198 | Água fria e quente - Distribuição 8
28362231 | Água fria e quente - Distribuição 8
28370612 | Água fria e quente - Distribuição 8
28370630 | Água fria e quente - Distribuição 8
28370908 | Irrigação 1
28370936 | Água fria e quente - Distribuição 8

# IfcFlowController: AF_Soldavel_Valvula de Retencao:Soldável - 50 mm, AF_Soldavel_Valvula de Retencao:Soldável - 50 mm:28403089
In: IMPLANTAÇÃO DRENAGEM
Type - Material: PVC Marrom
Type - Pset_ManufacturerTypeInformation - Manufacturer: © Tigre S/A
Pset_DistributionFlowElementCommon - Reference: Soldável - 50 mm; sets with these values: 2

# IfcFlowController: Bomba de recalque1:Bomba de recalque, Bomba de recalque1:Bomba de recalque:28362762
In: IMPLANTAÇÃO DRENAGEM
Type - Material: Steel - Franklin Electric - Green
Type - Pset_ManufacturerTypeInformation - Manufacturer: Franklin Electric
Classification: D3040 Distribution Systems (Uniformat)
Pset_DistributionFlowElementCommon - Reference: Bomba de recalque; sets with these values: 2

# IfcFlowController: Manômetro de Pressão:Mostrador de 50 mm - 8 mm, Manômetro de Pressão:Mostrador de 50 mm - 8 mm:28367458
In: IMPLANTAÇÃO DRENAGEM
Type - Material: Aço inox, Plástico preto, Plástico Vermelho, Latão, Vidro Mostrador
Pset_DistributionFlowElementCommon - Reference: Mostrador de 50 mm - 8 mm; sets with these values: 2
Group: Água fria e quente - Distribuição 14

# IfcFlowController: PVB_Professional_Series_10_Round_Valve_Box:10" Round Valve Box (5)
In: IMPLANTAÇÃO DRENAGEM
Type - Material: Black, Green
Pset_DistributionFlowElementCommon - Reference: 10" Round Valve Box; sets with these values: 2
Name (PVB_Professional_Series_10_Round_Valve_Box:10" Round Valve Box:...)
28350502
28359469
28359604
28359798
28359895

# IfcFlowController: Rotor_5000_Series_5006PC:Rain Curtain 5.0 (48)
In: IMPLANTAÇÃO DRENAGEM
Type - Material: Water, Black Plastic, Blue Plastic
Type - Pset_ManufacturerTypeInformation - Manufacturer: Rain Bird
Pset_DistributionFlowElementCommon - Reference: Rain Curtain 5.0; sets with these values: 2
Name (Rotor_5000_Series_5006PC:Rain Curtain 5.0:...)
28357355
28357933
28358086
28358103
28358118
28358133
28358146
28358209
28359486
28359492
28359498
28359504
28359510
28359516
28359522
28359528
28359621
28359627
28359633
28359639
28359645
28359651
28359657
28359663
28359718
28359724
28359730
28359736
28359742
28359748
28359754
28359760
28359815
28359821
28359827
28359833
28359839
28359845
28359851
28359857
28359912
28359918
28359924
28359930
28359936
28359942
28359948
28359954

# IfcFlowController: SA_Series (2):SA-6050 (48)
In: IMPLANTAÇÃO DRENAGEM
Type - Material: PLÁSTICO, PVC Azul
Pset_DistributionFlowElementCommon - Reference: SA-6050; sets with these values: 2
Name (SA_Series (2):SA-6050:...)
28357204
28357932
28358085
28358102
28358117
28358132
28358145
28358208
28359485
28359491
28359497
28359503
28359509
28359515
28359521
28359527
28359620
28359626
28359632
28359638
28359644
28359650
28359656
28359662
28359717
28359723
28359729
28359735
28359741
28359747
28359753
28359759
28359814
28359820
28359826
28359832
28359838
28359844
28359850
28359856
28359911
28359917
28359923
28359929
28359935
28359941
28359947
28359953

# IfcFlowController: Valve_PGA_Series_150PGA:150-PGA (6)
In: IMPLANTAÇÃO DRENAGEM
Type - Material: PVC-U, Aço cromado, <Unnamed>
Pset_DistributionFlowElementCommon - Reference: 150-PGA; sets with these values: 2
Name (Valve_PGA_Series_150PGA:150-PGA:...) | Group
28350503 | Água fria e quente - Distribuição 3
28359470 | Água fria e quente - Distribuição 1
28359605 | Água fria e quente - Distribuição 2
28359702 | Água fria e quente - Distribuição 4
28359799 | Água fria e quente - Distribuição 5
28359896 | Água fria e quente - Distribuição 6

# IfcFlowFitting: AF_Roscavel _Joelho 45_90:Standard (6)
In: IMPLANTAÇÃO DRENAGEM
Type - Material: PVC Branco
Type - Pset_ManufacturerTypeInformation - Manufacturer: © Tigre S/A
Pset_DistributionFlowElementCommon - Reference: Standard; sets with these values: 2
Name (AF_Roscavel _Joelho 45_90:Standard:...) | Group
28359193 | Irrigação 6
28359535 | Irrigação 24
28359670 | Irrigação 32
28359767 | Irrigação 41
28359864 | Irrigação 50
28359961 | Irrigação 59

# IfcFlowFitting: AF_Roscavel_Te_Reducao:Standard (43)
In: IMPLANTAÇÃO DRENAGEM
Type - Material: PVC Branco
Type - Pset_ManufacturerTypeInformation - Manufacturer: © Tigre S/A
Pset_DistributionFlowElementCommon - Reference: Standard; sets with these values: 2
Name (AF_Roscavel_Te_Reducao:Standard:...) | Group
28357600 | Irrigação 21
28357934 | Irrigação 21
28358087 | Irrigação 2
28358104 | Irrigação 3
28358119 | Irrigação 4
28358134 | Irrigação 5
28358147 | Irrigação 6
28359487 | Irrigação 11
28359493 | Irrigação 11
28359499 | Irrigação 15
28359505 | Irrigação 18
28359511 | Irrigação 20
28359517 | Irrigação 23
28359523 | Irrigação 24
28359622 | Irrigação 16
28359628 | Irrigação 16
28359634 | Irrigação 25
28359640 | Irrigação 27
28359646 | Irrigação 29
28359652 | Irrigação 31
28359658 | Irrigação 32
28359719 | Irrigação 28
28359725 | Irrigação 28
28359731 | Irrigação 34
28359737 | Irrigação 36
28359743 | Irrigação 38
28359749 | Irrigação 40
28359755 | Irrigação 41
28359816 | Irrigação 37
28359822 | Irrigação 37
28359828 | Irrigação 43
28359834 | Irrigação 45
28359840 | Irrigação 47
28359846 | Irrigação 49
28359852 | Irrigação 50
28359913 | Irrigação 46
28359919 | Irrigação 46
28359925 | Irrigação 52
28359931 | Irrigação 54
28359937 | Irrigação 56
28359943 | Irrigação 58
28359949 | Irrigação 59
28367899 | Irrigação 1

# IfcFlowFitting: AF_Soldavel_Adaptador Curto com Bolsa e Rosca:Standard (13)
In: IMPLANTAÇÃO DRENAGEM
Type - Material: PVC Marrom
Type - Pset_ManufacturerTypeInformation - Manufacturer: © Tigre S/A
Pset_DistributionFlowElementCommon - Reference: Standard; sets with these values: 2
Name (AF_Soldavel_Adaptador Curto com Bolsa e Rosca:Standard:...) | Group
28350504 | Irrigação 13
28350510 | Irrigação 17
28359471 | Irrigação 7
28359477 | Irrigação 9
28359606 | Irrigação 8
28359612 | Irrigação 12
28359703 | Irrigação 14
28359709 | Irrigação 22
28359800 | Irrigação 26
28359806 | Irrigação 33
28359897 | Irrigação 35
28359903 | Irrigação 42
28367805 | Irrigação 1

# IfcFlowFitting: AF_Soldavel_Bucha de Reducao Curta:Standard (6)
In: IMPLANTAÇÃO DRENAGEM
Type - Material: PVC Marrom
Type - Pset_ManufacturerTypeInformation - Manufacturer: © Tigre S/A
Pset_DistributionFlowElementCommon - Reference: Standard; sets with these values: 2
Name (AF_Soldavel_Bucha de Reducao Curta:Standard:...) | Group
28358702 | Irrigação 6
28359533 | Irrigação 24
28359668 | Irrigação 32
28359765 | Irrigação 41
28359862 | Irrigação 50
28359959 | Irrigação 59

# IfcFlowFitting: AF_Soldavel_Bucha de Reducao Longa:Standard (10)
In: IMPLANTAÇÃO DRENAGEM
Type - Material: PVC Marrom
Type - Pset_ManufacturerTypeInformation - Manufacturer: © Tigre S/A
Pset_DistributionFlowElementCommon - Reference: Standard; sets with these values: 2
Name (AF_Soldavel_Bucha de Reducao Longa:Standard:...) | Group
28351127 | Irrigação 1
28351626 | Irrigação 1
28358474 | Irrigação 5
28359531 | Irrigação 23
28359666 | Irrigação 31
28359763 | Irrigação 40
28359860 | Irrigação 49
28359957 | Irrigação 58
28363578 | Água fria e quente - Distribuição 8
28368012 | Irrigação 1

# IfcFlowFitting: AF_Soldavel_Curva 45_90:Standard (9)
In: IMPLANTAÇÃO DRENAGEM
Type - Material: PVC Marrom
Type - Pset_ManufacturerTypeInformation - Manufacturer: © Tigre S/A
Pset_DistributionFlowElementCommon - Reference: Standard; sets with these values: 2
Name (AF_Soldavel_Curva 45_90:Standard:...) | Group
28332008 | Irrigação 1
28351133 | Irrigação 1
28351624 | Irrigação 1
28362969 | Água fria e quente - Distribuição 8
28362979 | Água fria e quente - Distribuição 8
28368008 | Irrigação 1
28368110 | Irrigação 1
28368114 | Irrigação 1
28368186 | Irrigação 1

# IfcFlowFitting: AF_Soldavel_Joelho 45_90:Standard (6)
In: IMPLANTAÇÃO DRENAGEM
Type - Material: PVC Marrom
Type - Pset_ManufacturerTypeInformation - Manufacturer: © Tigre S/A
Pset_DistributionFlowElementCommon - Reference: Standard; sets with these values: 2
Name (AF_Soldavel_Joelho 45_90:Standard:...) | Group
28370257 | Água fria e quente - Distribuição 8
28370259 | Água fria e quente - Distribuição 8
28371330 | Água fria e quente - Distribuição 9
28371332 | Água fria e quente - Distribuição 9
28371464 | Água fria e quente - Distribuição 8
28371736 | Água fria e quente - Distribuição 8

# IfcFlowFitting: AF_Soldavel_Te_Reducao:Standard (10)
In: IMPLANTAÇÃO DRENAGEM
Type - Material: PVC Marrom
Type - Pset_ManufacturerTypeInformation - Manufacturer: © Tigre S/A
Pset_DistributionFlowElementCommon - Reference: Standard; sets with these values: 2
Name (AF_Soldavel_Te_Reducao:Standard:...) | Group
28332204 | Irrigação 1
28359577 | Irrigação 1
28360007 | Irrigação 1
28360027 | Irrigação 1
28360045 | Irrigação 1
28362554 | Água fria e quente - Distribuição 8
28370279 | Água fria e quente - Distribuição 8
28371173 | Água fria e quente - Distribuição 8
28371628 | Água fria e quente - Distribuição 8
28372723 | Água fria e quente - Distribuição 9

# IfcFlowFitting: AF_Soldavel_Uniao:Standard (14)
In: IMPLANTAÇÃO DRENAGEM
Type - Material: PVC Marrom
Type - Pset_ManufacturerTypeInformation - Manufacturer: © Tigre S/A
Pset_DistributionFlowElementCommon - Reference: Standard; sets with these values: 2
Name (AF_Soldavel_Uniao:Standard:...) | Group
28350508 | Irrigação 1
28350512 | Irrigação 21
28359475 | Irrigação 1
28359479 | Irrigação 11
28359610 | Irrigação 1
28359614 | Irrigação 16
28359707 | Irrigação 1
28359711 | Irrigação 28
28359804 | Irrigação 1
28359808 | Irrigação 37
28359901 | Irrigação 39
28359905 | Irrigação 46
28363624 | Água fria e quente - Distribuição 8
28367871 | Irrigação 1

# IfcFlowFitting: AN_PLUV_Anel de vedação para Conexão Série R:AN_PLUV_Anel de vedação para Conexão Série R (84)
In: IMPLANTAÇÃO DRENAGEM
Type - Material: Borracha
Type - Pset_ManufacturerTypeInformation - Manufacturer: Blukit
Pset_DistributionFlowElementCommon - Reference: AN_PLUV_Anel de vedação para Conexão Série R; sets with these values: 2
Name (AN_PLUV_Anel de vedação para Conexão Série R:AN_PLUV_Anel de vedação para Conexão Série R:...)
28413116
28413118
28413120
28413126
28413128
28413130
28413459
28413461
28413463
28413469
28413471
28413473
28413523
28413525
28413527
28413533
28413535
28413537
28413576
28413578
28413580
28413586
28413588
28413590
28413619
28413621
28413623
28413629
28413631
28413633
28413725
28413727
28413729
28413735
28413737
28413739
28413851
28413853
28413855
28413861
28413863
28413865
28413904
28413906
28413908
28413914
28413916
28413918
28413924
28413926
28413928
28413934
28413936
28413938
28413944
28413946
28413948
28413954
28413956
28413958
28413964
28413966
28413968
28413974
28413976
28413978
28413984
28413986
28413988
28413994
28413996
28413998
28414004
28414006
28414008
28414014
28414016
28414018
28414024
28414026
28414028
28414034
28414036
28414038

# IfcFlowFitting: Adaptador Soldavel com Anel para CxDagua - Fortlev:Standard (8)
In: IMPLANTAÇÃO DRENAGEM
Type - Material: Fortlev - PVC Marrom
Type - Pset_ManufacturerTypeInformation - Manufacturer: Fortlev
Pset_DistributionFlowElementCommon - Reference: Standard; sets with these values: 2
Name (Adaptador Soldavel com Anel para CxDagua - Fortlev:Standard:...)
28360371
28360375
28360496
28418382
28418450
28418604
28419284
28419288

# IfcFlowFitting: PLUV_Serie Reforcada_Luva Simples:Standard (28)
In: IMPLANTAÇÃO DRENAGEM
Type - Material: PVC Bege Pérola
Type - Pset_ManufacturerTypeInformation - Manufacturer: © Tigre S/A
Pset_DistributionFlowElementCommon - Reference: Standard; sets with these values: 2
Name (PLUV_Serie Reforcada_Luva Simples:Standard:...)
28413114
28413124
28413457
28413467
28413521
28413531
28413574
28413584
28413617
28413627
28413723
28413733
28413849
28413859
28413902
28413912
28413922
28413932
28413942
28413952
28413962
28413972
28413982
28413992
28414002
28414012
28414022
28414032

# IfcFlowFitting: PLUV_Serie Reforcada_Te_Juncao:Standard (28)
In: IMPLANTAÇÃO DRENAGEM
Type - Material: PVC Bege Pérola
Type - Pset_ManufacturerTypeInformation - Manufacturer: © Tigre S/A
Pset_DistributionFlowElementCommon - Reference: Standard; sets with these values: 2
Name (PLUV_Serie Reforcada_Te_Juncao:Standard:...) | Group
28413112 | Outro 45
28413122 | Outro 46
28413455 | Outro 43
28413465 | Outro 44
28413519 | Outro 41
28413529 | Outro 42
28413572 | Outro 39
28413582 | Outro 40
28413615 | Outro 37
28413625 | Outro 38
28413721 | Outro 47
28413731 | Outro 48
28413847 | Outro 31
28413857 | Outro 32
28413900 | Outro 33
28413910 | Outro 34
28413920 | Outro 35
28413930 | Outro 36
28413940 | Outro 49
28413950 | Outro 50
28413960 | Outro 51
28413970 | Outro 52
28413980 | Outro 53
28413990 | Outro 54
28414000 | Outro 55
28414010 | Outro 56
28414020 | Outro 57
28414030 | Outro 58

# IfcFlowSegment: Tipos de tubos:AF_Tubo Branco Roscável (18)
In: IMPLANTAÇÃO DRENAGEM
Type - Pset_ManufacturerTypeInformation - Manufacturer: Tigre S.A.
Pset_DistributionFlowElementCommon - Reference: AF_Tubo Branco Roscável; sets with these values: 2
Pset_FlowSegmentDuctSegment - sets with these values: 2
Name (Tipos de tubos:AF_Tubo Branco Roscável:...) | Length (m) | Group
28362092 | 0.108393 | Água fria e quente - Distribuição 8
28362131 | 0.0641547 | Água fria e quente - Distribuição 8
28362200 | 0.106746 | Água fria e quente - Distribuição 8
28362233 | 0.0625071 | Água fria e quente - Distribuição 8
28362430 | 0.4095 | Água fria e quente - Distribuição 8
28370243 | 1.893 | Água fria e quente - Distribuição 8
28370267 | 0.1534 | Água fria e quente - Distribuição 8
28370280 | 1.899 | Água fria e quente - Distribuição 8
28371160 | 0.0775668 | Água fria e quente - Distribuição 8
28371192 | 0.48 | Água fria e quente - Distribuição 8
28371257 | 0.392771 | Água fria e quente - Distribuição 9
28371298 | 0.392771 | Água fria e quente - Distribuição 9
28371310 | 1.90654 | Água fria e quente - Distribuição 9
28371603 | 2.226 | Água fria e quente - Distribuição 8
28371629 | 0.4155 | Água fria e quente - Distribuição 8
28371674 | 2.07297 | Água fria e quente - Distribuição 8
28372707 | 0.6205 | Água fria e quente - Distribuição 9
28372724 | 1.91586 | Água fria e quente - Distribuição 9

# IfcFlowSegment: Tipos de tubos:AF_Tubo Marrom Soldável (92)
In: IMPLANTAÇÃO DRENAGEM
Type - Pset_ManufacturerTypeInformation - Manufacturer: Tigre S.A.
Pset_DistributionFlowElementCommon - Reference: AF_Tubo Marrom Soldável; sets with these values: 2
Pset_FlowSegmentDuctSegment - sets with these values: 2
Name (Tipos de tubos:AF_Tubo Marrom Soldável:...) | Length (m) | Group
28331878 | 6.34029 | Irrigação 1
28331994 | 8.10644 | Irrigação 1
28332002 | 1.42884 | Irrigação 1
28332010 | 13.0307 | Irrigação 1
28332215 | 7.35663 | Irrigação 1
28350506 | 2.53785 | Irrigação 1
28350514 | 0.148344 | Irrigação 1
28350516 | 0.167618 | Irrigação 21
28351550 | 5.62477 | Irrigação 1
28357601 | 3.81879 | Irrigação 21
28358009 | 12.9348 | Irrigação 21
28358089 | 12.9348 | Irrigação 2
28358106 | 12.9348 | Irrigação 3
28358121 | 12.9348 | Irrigação 4
28358136 | 12.9039 | Irrigação 5
28358149 | 12.9584 | Irrigação 6
28358212 | 12.9661 | Irrigação 6
28359473 | 2.6719 | Irrigação 1
28359481 | 0.148344 | Irrigação 1
28359483 | 0.167618 | Irrigação 11
28359488 | 3.81879 | Irrigação 11
28359495 | 12.9348 | Irrigação 11
28359501 | 12.9348 | Irrigação 15
28359507 | 12.9348 | Irrigação 18
28359513 | 12.9348 | Irrigação 20
28359519 | 12.9339 | Irrigação 23
28359525 | 12.9284 | Irrigação 24
28359529 | 12.9336 | Irrigação 24
28359578 | 13.0307 | Irrigação 1
28359608 | 2.6719 | Irrigação 1
28359616 | 0.148344 | Irrigação 1
28359618 | 0.167618 | Irrigação 16
28359623 | 3.81879 | Irrigação 16
28359630 | 12.9348 | Irrigação 16
28359636 | 12.9348 | Irrigação 25
28359642 | 12.9348 | Irrigação 27
28359648 | 12.9348 | Irrigação 29
28359654 | 12.9339 | Irrigação 31
28359660 | 12.9284 | Irrigação 32
28359664 | 12.9336 | Irrigação 32
28359705 | 2.6719 | Irrigação 1
28359713 | 0.148344 | Irrigação 1
28359715 | 0.167618 | Irrigação 28
28359720 | 3.81879 | Irrigação 28
28359727 | 12.9348 | Irrigação 28
28359733 | 12.9348 | Irrigação 34
28359739 | 12.9348 | Irrigação 36
28359745 | 12.9348 | Irrigação 38
28359751 | 12.9339 | Irrigação 40
28359757 | 12.9284 | Irrigação 41
28359761 | 12.9336 | Irrigação 41
28359802 | 2.6719 | Irrigação 1
28359810 | 0.148344 | Irrigação 1
28359812 | 0.167618 | Irrigação 37
28359817 | 3.81879 | Irrigação 37
28359824 | 12.9348 | Irrigação 37
28359830 | 12.9348 | Irrigação 43
28359836 | 12.9348 | Irrigação 45
28359842 | 12.9348 | Irrigação 47
28359848 | 12.9339 | Irrigação 49
28359854 | 12.9284 | Irrigação 50
28359858 | 12.9336 | Irrigação 50
28359899 | 2.6119 | Irrigação 39
28359907 | 0.148344 | Irrigação 39
28359909 | 0.167618 | Irrigação 46
28359914 | 3.81879 | Irrigação 46
28359921 | 12.9348 | Irrigação 46
28359927 | 12.9348 | Irrigação 52
28359933 | 12.9348 | Irrigação 54
28359939 | 12.9348 | Irrigação 56
28359945 | 12.9339 | Irrigação 58
28359951 | 12.9284 | Irrigação 59
28359955 | 12.9336 | Irrigação 59
28360028 | 13.092 | Irrigação 1
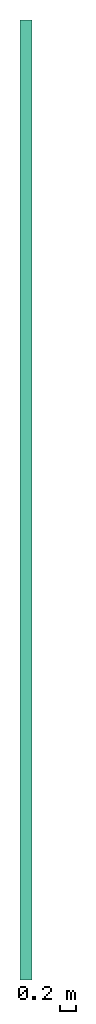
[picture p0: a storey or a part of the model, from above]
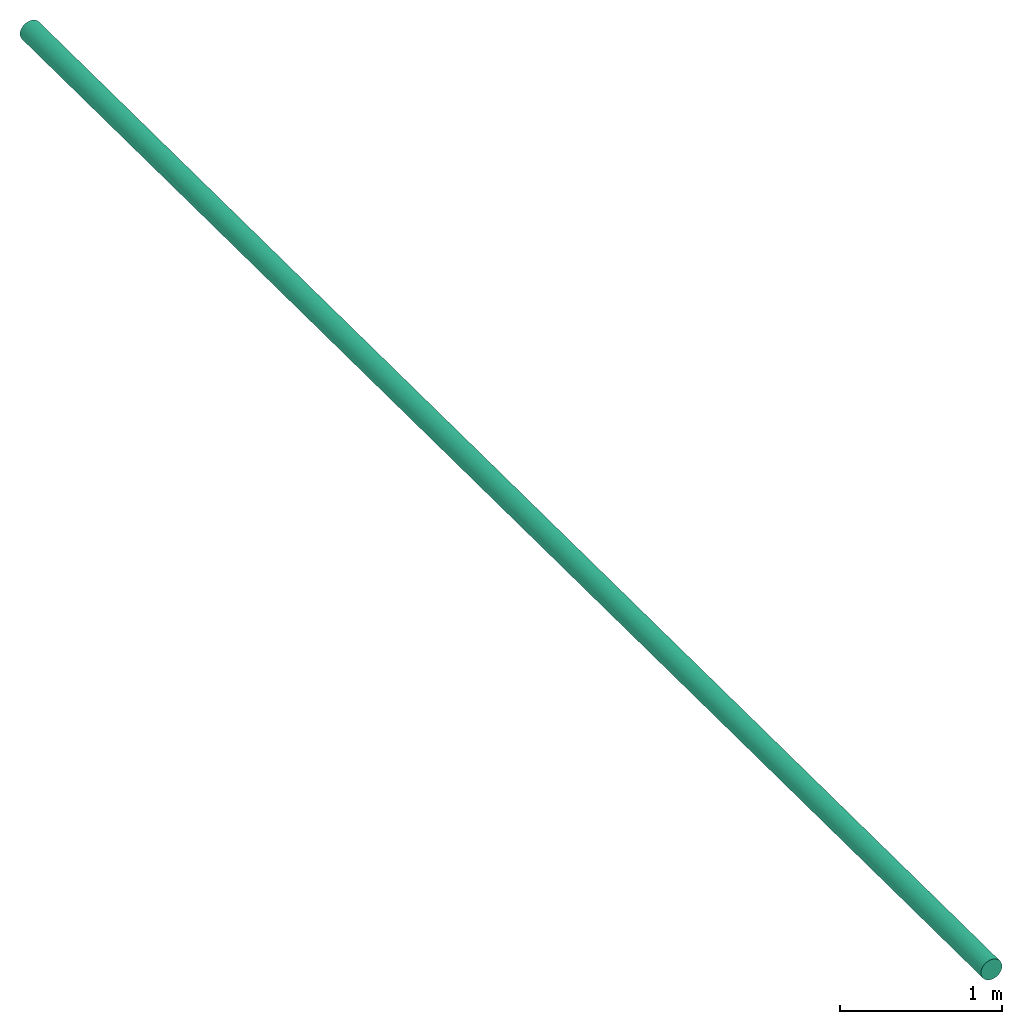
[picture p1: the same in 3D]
Properties of the parts of a building model (IFC2X3), part 2 of 2

# IfcFlowSegment: Tipos de tubos:AF_Tubo Marrom Soldável (92)
Name (Tipos de tubos:AF_Tubo Marrom Soldável:...) | Length (m) | Group
28360046 | 13.092 | Irrigação 1
28362357 | 0.0288581 | Água fria e quente - Distribuição 8
28362555 | 0.232581 | Água fria e quente - Distribuição 8
28362955 | 1.46053 | Água fria e quente - Distribuição 8
28362961 | 0.348745 | Água fria e quente - Distribuição 8
28363414 | 0.0743452 | Água fria e quente - Distribuição 8
28363507 | 0.00500012 | Água fria e quente - Distribuição 8
28363627 | 0.117837 | Água fria e quente - Distribuição 8
28364081 | 0.0921347 | Irrigação 1
28364225 | 0.0295177 | Irrigação 1
28367874 | 0.0486848 | Irrigação 1
28367900 | 0.126415 | Irrigação 1
28367967 | 0.417472 | Irrigação 1
28368108 | 1.16948 | Irrigação 1
28370614 | 0.222072 | Água fria e quente - Distribuição 8
28370632 | 0.0243491 | Água fria e quente - Distribuição 8
28370910 | 0.0512753 | Irrigação 1
28370938 | 6.62746 | Água fria e quente - Distribuição 8

# IfcFlowSegment: Tipos de tubos:PLUV_Tubo PEAD Corrugado (30)
In: IMPLANTAÇÃO DRENAGEM
Type - Pset_ManufacturerTypeInformation - Manufacturer: Tigre S.A.
Pset_DistributionFlowElementCommon - Reference: PLUV_Tubo PEAD Corrugado; sets with these values: 2
Pset_FlowSegmentDuctSegment - sets with these values: 2
Name (Tipos de tubos:PLUV_Tubo PEAD Corrugado:...) | Length (m) | Group
28303643 | 24.4802 | Outro 1
28304500 | 24.4802 | Outro 2
28304754 | 24.4802 | Outro 5
28304825 | 24.4802 | Outro 4
28304847 | 24.4802 | Outro 8
28304869 | 24.4802 | Outro 10
28304983 | 24.4802 | Outro 7
28304996 | 24.4802 | Outro 9
28305340 | 72.297 | Outro 18
28308791 | 24.4802 | Outro 17
28309445 | 24.4802 | Outro 6
28309447 | 24.4802 | Outro 11
28309449 | 24.4802 | Outro 12
28309451 | 24.4802 | Outro 13
28309453 | 24.4802 | Outro 14
28309455 | 24.4802 | Outro 15
28309488 | 24.4802 | Outro 16
28309490 | 24.4802 | Outro 19
28309492 | 24.4802 | Outro 20
28309494 | 24.4802 | Outro 21
28309496 | 24.4802 | Outro 22
28309498 | 24.4802 | Outro 23
28309500 | 24.4802 | Outro 24
28309502 | 24.4802 | Outro 25
28309504 | 24.4802 | Outro 26
28309506 | 24.4802 | Outro 27
28309508 | 24.4802 | Outro 28
28309510 | 24.4802 | Outro 29
28309580 | 24.4802 | Outro 30
28416132 | 72.297 | Outro 59

# IfcFlowSegment: Tipos de tubos:PLUV_Tubo Série Reforçada (5)
Type - Pset_ManufacturerTypeInformation - Manufacturer: Tigre S.A.
Pset_DistributionFlowElementCommon - Reference: PLUV_Tubo Série Reforçada; sets with these values: 2
Pset_FlowSegmentDuctSegment - sets with these values: 2
Name (Tipos de tubos:PLUV_Tubo Série Reforçada:...) | In | Length (m) | Group
28311791 | IMPLANTAÇÃO DRENAGEM | 43.972 | Pluvial 1
28312506 | IMPLANTAÇÃO DRENAGEM | 33.0016 | Pluvial 2
28313325 | IMPLANTAÇÃO DRENAGEM | 11.891 | Pluvial 4
28313540 | NIVEL 0 | 11.891 | Pluvial 5
28415915 | IMPLANTAÇÃO DRENAGEM | 33.0016 | Pluvial 6

# IfcFlowTerminal: Controller_ESP-LXME:Quadro de Comando e Controlador - IESP8LXME, Controller_ESP-LXME:Quadro de Comando e Controlador - IESP8LXME:28396927
In: IMPLANTAÇÃO DRENAGEM
Type - Material: BRANCO, <Unnamed>
Pset_DistributionFlowElementCommon - Reference: Quadro de Comando e Controlador - IESP8LXME; sets with these values: 2

# IfcFlowTerminal: Controller_TBOS-BT:Sensor de Chuva, Controller_TBOS-BT:Sensor de Chuva:28396174
In: IMPLANTAÇÃO DRENAGEM
Type - Material: Black, Blue
Pset_DistributionFlowElementCommon - Reference: Sensor de Chuva; sets with these values: 2

# IfcFlowTerminal: Tanque Fortlev - 2000 a 20.000 Litros:20000 Litros (2)
In: IMPLANTAÇÃO DRENAGEM
Type - Material: Fortlev - Tanque - Plástico Preto, Fortlev - Tanque - Plástico Azul
Type - Pset_ManufacturerTypeInformation - Manufacturer: Fortlev
Pset_DistributionFlowElementCommon - Reference: 20000 Litros; sets with these values: 2
Name (Tanque Fortlev - 2000 a 20.000 Litros:20000 Litros:...) | Group
28360117 | Água fria e quente - Distribuição 8; Água fria e quente - Distribuição 9; Água fria e quente - Distribuição 11; Água fria e quente - Distribuição 7
28360491 | Água fria e quente - Distribuição 8; Água fria e quente - Distribuição 9; Água fria e quente - Distribuição 10

# IfcWall: Parede básica:BRITA - 40 CM (26)
In: IMPLANTAÇÃO DRENAGEM
Type - PredefinedType: STANDARD; Material: Generic 0.5 m
Pset_QuantityTakeOff - Reference: BRITA - 40 CM; sets with these values: 2
Pset_WallCommon - Reference: BRITA - 40 CM; IsExternal: yes; ExtendToStructure: no; LoadBearing: no
Name (Parede básica:BRITA - 40 CM:...)
28306893
28307034
28307171
28307305
28307363
28307424
28308127
28308144
28308161
28308178
28308195
28308212
28308229
28308817
28308829
28308841
28308853
28308865
28308877
28308889
28308913
28308925
28308937
28308949
28308961
28308973

# IfcWallStandardCase: Parede básica:BRITA - 40 CM (4)
In: IMPLANTAÇÃO DRENAGEM
Type - PredefinedType: STANDARD; Material: Generic 0.5 m
Pset_QuantityTakeOff - Reference: BRITA - 40 CM; sets with these values: 2
Pset_WallCommon - Reference: BRITA - 40 CM; IsExternal: yes; ExtendToStructure: no; LoadBearing: no
Name (Parede básica:BRITA - 40 CM:...)
28305579
28308901
28309656
28310634
